VERSION 5.7 ;
  NOWIREEXTENSIONATPIN ON ;
  DIVIDERCHAR "/" ;
  BUSBITCHARS "[]" ;
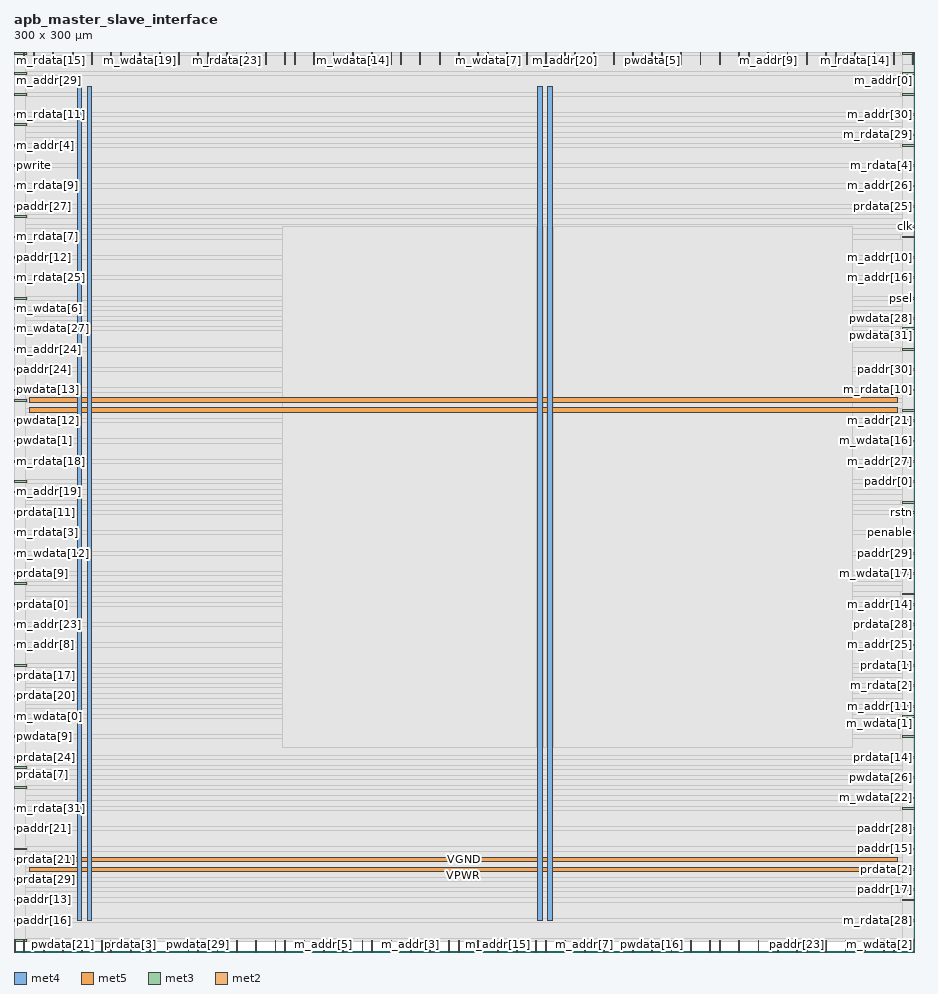
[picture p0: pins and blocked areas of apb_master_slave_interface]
MACRO apb_master_slave_interface
  CLASS BLOCK ;
  FOREIGN apb_master_slave_interface ;
  ORIGIN 0.000 0.000 ;
  SIZE 300.000 BY 300.000 ;
  PIN VGND
    DIRECTION INOUT ;
    USE GROUND ;
    PORT
      LAYER met4 ;
        RECT 24.340 10.640 25.940 288.560 ;
    END
    PORT
      LAYER met4 ;
        RECT 177.940 10.640 179.540 288.560 ;
    END
    PORT
      LAYER met5 ;
        RECT 5.280 30.030 294.640 31.630 ;
    END
    PORT
      LAYER met5 ;
        RECT 5.280 183.210 294.640 184.810 ;
    END
  END VGND
  PIN VPWR
    DIRECTION INOUT ;
    USE POWER ;
    PORT
      LAYER met4 ;
        RECT 21.040 10.640 22.640 288.560 ;
    END
    PORT
      LAYER met4 ;
        RECT 174.640 10.640 176.240 288.560 ;
    END
    PORT
      LAYER met5 ;
        RECT 5.280 26.730 294.640 28.330 ;
    END
    PORT
      LAYER met5 ;
        RECT 5.280 179.910 294.640 181.510 ;
    END
  END VPWR
  PIN clk
    DIRECTION INPUT ;
    USE SIGNAL ;
    ANTENNAGATEAREA 0.852000 ;
    PORT
      LAYER met3 ;
        RECT 296.000 241.440 300.000 242.040 ;
    END
  END clk
  PIN m_addr[0]
    DIRECTION INPUT ;
    USE SIGNAL ;
    ANTENNAGATEAREA 0.196500 ;
    PORT
      LAYER met3 ;
        RECT 296.000 292.440 300.000 293.040 ;
    END
  END m_addr[0]
  PIN m_addr[10]
    DIRECTION INPUT ;
    USE SIGNAL ;
    ANTENNAGATEAREA 0.196500 ;
    PORT
      LAYER met3 ;
        RECT 296.000 231.240 300.000 231.840 ;
    END
  END m_addr[10]
  PIN m_addr[11]
    DIRECTION INPUT ;
    USE SIGNAL ;
    ANTENNAGATEAREA 0.196500 ;
    PORT
      LAYER met3 ;
        RECT 296.000 81.640 300.000 82.240 ;
    END
  END m_addr[11]
  PIN m_addr[12]
    DIRECTION INPUT ;
    USE SIGNAL ;
    ANTENNAGATEAREA 0.196500 ;
    PORT
      LAYER met3 ;
        RECT 296.000 149.640 300.000 150.240 ;
    END
  END m_addr[12]
  PIN m_addr[13]
    DIRECTION INPUT ;
    USE SIGNAL ;
    ANTENNAGATEAREA 0.196500 ;
    PORT
      LAYER met2 ;
        RECT 283.450 0.000 283.730 4.000 ;
    END
  END m_addr[13]
  PIN m_addr[14]
    DIRECTION INPUT ;
    USE SIGNAL ;
    ANTENNAGATEAREA 0.196500 ;
    PORT
      LAYER met3 ;
        RECT 296.000 115.640 300.000 116.240 ;
    END
  END m_addr[14]
  PIN m_addr[15]
    DIRECTION INPUT ;
    USE SIGNAL ;
    ANTENNAGATEAREA 0.196500 ;
    PORT
      LAYER met2 ;
        RECT 161.090 0.000 161.370 4.000 ;
    END
  END m_addr[15]
  PIN m_addr[16]
    DIRECTION INPUT ;
    USE SIGNAL ;
    ANTENNAGATEAREA 0.126000 ;
    PORT
      LAYER met3 ;
        RECT 296.000 224.440 300.000 225.040 ;
    END
  END m_addr[16]
  PIN m_addr[17]
    DIRECTION INPUT ;
    USE SIGNAL ;
    ANTENNAGATEAREA 0.213000 ;
    PORT
      LAYER met2 ;
        RECT 83.810 296.000 84.090 300.000 ;
    END
  END m_addr[17]
  PIN m_addr[18]
    DIRECTION INPUT ;
    USE SIGNAL ;
    ANTENNAGATEAREA 0.213000 ;
    PORT
      LAYER met2 ;
        RECT 270.570 0.000 270.850 4.000 ;
    END
  END m_addr[18]
  PIN m_addr[19]
    DIRECTION INPUT ;
    USE SIGNAL ;
    ANTENNAGATEAREA 0.196500 ;
    PORT
      LAYER met3 ;
        RECT 0.000 153.040 4.000 153.640 ;
    END
  END m_addr[19]
  PIN m_addr[1]
    DIRECTION INPUT ;
    USE SIGNAL ;
    ANTENNAGATEAREA 0.196500 ;
    PORT
      LAYER met2 ;
        RECT 54.830 296.000 55.110 300.000 ;
    END
  END m_addr[1]
  PIN m_addr[20]
    DIRECTION INPUT ;
    USE SIGNAL ;
    ANTENNAGATEAREA 0.196500 ;
    PORT
      LAYER met2 ;
        RECT 183.630 296.000 183.910 300.000 ;
    END
  END m_addr[20]
  PIN m_addr[21]
    DIRECTION INPUT ;
    USE SIGNAL ;
    ANTENNAGATEAREA 0.126000 ;
    PORT
      LAYER met3 ;
        RECT 296.000 176.840 300.000 177.440 ;
    END
  END m_addr[21]
  PIN m_addr[22]
    DIRECTION INPUT ;
    USE SIGNAL ;
    ANTENNAGATEAREA 0.213000 ;
    PORT
      LAYER met2 ;
        RECT 241.590 0.000 241.870 4.000 ;
    END
  END m_addr[22]
  PIN m_addr[23]
    DIRECTION INPUT ;
    USE SIGNAL ;
    ANTENNAGATEAREA 0.196500 ;
    PORT
      LAYER met3 ;
        RECT 0.000 108.840 4.000 109.440 ;
    END
  END m_addr[23]
  PIN m_addr[24]
    DIRECTION INPUT ;
    USE SIGNAL ;
    ANTENNAGATEAREA 0.196500 ;
    PORT
      LAYER met3 ;
        RECT 0.000 200.640 4.000 201.240 ;
    END
  END m_addr[24]
  PIN m_addr[25]
    DIRECTION INPUT ;
    USE SIGNAL ;
    ANTENNAGATEAREA 0.126000 ;
    PORT
      LAYER met3 ;
        RECT 296.000 102.040 300.000 102.640 ;
    END
  END m_addr[25]
  PIN m_addr[26]
    DIRECTION INPUT ;
    USE SIGNAL ;
    ANTENNAGATEAREA 0.213000 ;
    PORT
      LAYER met3 ;
        RECT 296.000 255.040 300.000 255.640 ;
    END
  END m_addr[26]
  PIN m_addr[27]
    DIRECTION INPUT ;
    USE SIGNAL ;
    ANTENNAGATEAREA 0.196500 ;
    PORT
      LAYER met3 ;
        RECT 296.000 163.240 300.000 163.840 ;
    END
  END m_addr[27]
  PIN m_addr[28]
    DIRECTION INPUT ;
    USE SIGNAL ;
    ANTENNAGATEAREA 0.213000 ;
    PORT
      LAYER met3 ;
        RECT 0.000 183.640 4.000 184.240 ;
    END
  END m_addr[28]
  PIN m_addr[29]
    DIRECTION INPUT ;
    USE SIGNAL ;
    ANTENNAGATEAREA 0.159000 ;
    PORT
      LAYER met3 ;
        RECT 0.000 292.440 4.000 293.040 ;
    END
  END m_addr[29]
  PIN m_addr[2]
    DIRECTION INPUT ;
    USE SIGNAL ;
    ANTENNAGATEAREA 0.196500 ;
    PORT
      LAYER met2 ;
        RECT 90.250 296.000 90.530 300.000 ;
    END
  END m_addr[2]
  PIN m_addr[30]
    DIRECTION INPUT ;
    USE SIGNAL ;
    ANTENNAGATEAREA 0.196500 ;
    PORT
      LAYER met3 ;
        RECT 296.000 278.840 300.000 279.440 ;
    END
  END m_addr[30]
  PIN m_addr[31]
    DIRECTION INPUT ;
    USE SIGNAL ;
    ANTENNAGATEAREA 0.196500 ;
    PORT
      LAYER met2 ;
        RECT 80.590 0.000 80.870 4.000 ;
    END
  END m_addr[31]
  PIN m_addr[3]
    DIRECTION INPUT ;
    USE SIGNAL ;
    ANTENNAGATEAREA 0.196500 ;
    PORT
      LAYER met2 ;
        RECT 132.110 0.000 132.390 4.000 ;
    END
  END m_addr[3]
  PIN m_addr[4]
    DIRECTION INPUT ;
    USE SIGNAL ;
    ANTENNAGATEAREA 0.196500 ;
    PORT
      LAYER met3 ;
        RECT 0.000 268.640 4.000 269.240 ;
    END
  END m_addr[4]
  PIN m_addr[5]
    DIRECTION INPUT ;
    USE SIGNAL ;
    ANTENNAGATEAREA 0.196500 ;
    PORT
      LAYER met2 ;
        RECT 103.130 0.000 103.410 4.000 ;
    END
  END m_addr[5]
  PIN m_addr[6]
    DIRECTION INPUT ;
    USE SIGNAL ;
    ANTENNAGATEAREA 0.196500 ;
    PORT
      LAYER met2 ;
        RECT 128.890 296.000 129.170 300.000 ;
    END
  END m_addr[6]
  PIN m_addr[7]
    DIRECTION INPUT ;
    USE SIGNAL ;
    ANTENNAGATEAREA 0.196500 ;
    PORT
      LAYER met2 ;
        RECT 190.070 0.000 190.350 4.000 ;
    END
  END m_addr[7]
  PIN m_addr[8]
    DIRECTION INPUT ;
    USE SIGNAL ;
    ANTENNAGATEAREA 0.213000 ;
    PORT
      LAYER met3 ;
        RECT 0.000 102.040 4.000 102.640 ;
    END
  END m_addr[8]
  PIN m_addr[9]
    DIRECTION INPUT ;
    USE SIGNAL ;
    ANTENNAGATEAREA 0.196500 ;
    PORT
      LAYER met2 ;
        RECT 251.250 296.000 251.530 300.000 ;
    END
  END m_addr[9]
  PIN m_rdata[0]
    DIRECTION OUTPUT TRISTATE ;
    USE SIGNAL ;
    ANTENNADIFFAREA 0.795200 ;
    PORT
      LAYER met2 ;
        RECT 125.670 296.000 125.950 300.000 ;
    END
  END m_rdata[0]
  PIN m_rdata[10]
    DIRECTION OUTPUT TRISTATE ;
    USE SIGNAL ;
    ANTENNADIFFAREA 0.795200 ;
    PORT
      LAYER met3 ;
        RECT 296.000 187.040 300.000 187.640 ;
    END
  END m_rdata[10]
  PIN m_rdata[11]
    DIRECTION OUTPUT TRISTATE ;
    USE SIGNAL ;
    ANTENNADIFFAREA 0.795200 ;
    PORT
      LAYER met3 ;
        RECT 0.000 278.840 4.000 279.440 ;
    END
  END m_rdata[11]
  PIN m_rdata[12]
    DIRECTION OUTPUT TRISTATE ;
    USE SIGNAL ;
    ANTENNADIFFAREA 0.795200 ;
    PORT
      LAYER met2 ;
        RECT 99.910 296.000 100.190 300.000 ;
    END
  END m_rdata[12]
  PIN m_rdata[13]
    DIRECTION OUTPUT TRISTATE ;
    USE SIGNAL ;
    ANTENNADIFFAREA 0.795200 ;
    PORT
      LAYER met3 ;
        RECT 0.000 95.240 4.000 95.840 ;
    END
  END m_rdata[13]
  PIN m_rdata[14]
    DIRECTION OUTPUT TRISTATE ;
    USE SIGNAL ;
    ANTENNADIFFAREA 0.795200 ;
    PORT
      LAYER met2 ;
        RECT 280.230 296.000 280.510 300.000 ;
    END
  END m_rdata[14]
  PIN m_rdata[15]
    DIRECTION OUTPUT TRISTATE ;
    USE SIGNAL ;
    ANTENNADIFFAREA 0.795200 ;
    PORT
      LAYER met2 ;
        RECT 6.530 296.000 6.810 300.000 ;
    END
  END m_rdata[15]
  PIN m_rdata[16]
    DIRECTION OUTPUT TRISTATE ;
    USE SIGNAL ;
    ANTENNADIFFAREA 0.795200 ;
    PORT
      LAYER met2 ;
        RECT 144.990 0.000 145.270 4.000 ;
    END
  END m_rdata[16]
  PIN m_rdata[17]
    DIRECTION OUTPUT TRISTATE ;
    USE SIGNAL ;
    ANTENNADIFFAREA 0.795200 ;
    PORT
      LAYER met2 ;
        RECT 202.950 0.000 203.230 4.000 ;
    END
  END m_rdata[17]
  PIN m_rdata[18]
    DIRECTION OUTPUT TRISTATE ;
    USE SIGNAL ;
    ANTENNADIFFAREA 0.795200 ;
    PORT
      LAYER met3 ;
        RECT 0.000 163.240 4.000 163.840 ;
    END
  END m_rdata[18]
  PIN m_rdata[19]
    DIRECTION OUTPUT TRISTATE ;
    USE SIGNAL ;
    ANTENNADIFFAREA 0.795200 ;
    PORT
      LAYER met2 ;
        RECT 231.930 0.000 232.210 4.000 ;
    END
  END m_rdata[19]
  PIN m_rdata[1]
    DIRECTION OUTPUT TRISTATE ;
    USE SIGNAL ;
    ANTENNADIFFAREA 0.795200 ;
    PORT
      LAYER met2 ;
        RECT 29.070 0.000 29.350 4.000 ;
    END
  END m_rdata[1]
  PIN m_rdata[20]
    DIRECTION OUTPUT TRISTATE ;
    USE SIGNAL ;
    ANTENNADIFFAREA 0.795200 ;
    PORT
      LAYER met2 ;
        RECT 228.710 296.000 228.990 300.000 ;
    END
  END m_rdata[20]
  PIN m_rdata[21]
    DIRECTION OUTPUT TRISTATE ;
    USE SIGNAL ;
    ANTENNADIFFAREA 0.795200 ;
    PORT
      LAYER met2 ;
        RECT 90.250 0.000 90.530 4.000 ;
    END
  END m_rdata[21]
  PIN m_rdata[22]
    DIRECTION OUTPUT TRISTATE ;
    USE SIGNAL ;
    ANTENNADIFFAREA 0.795200 ;
    PORT
      LAYER met2 ;
        RECT 119.230 296.000 119.510 300.000 ;
    END
  END m_rdata[22]
  PIN m_rdata[23]
    DIRECTION OUTPUT TRISTATE ;
    USE SIGNAL ;
    ANTENNADIFFAREA 0.795200 ;
    PORT
      LAYER met2 ;
        RECT 70.930 296.000 71.210 300.000 ;
    END
  END m_rdata[23]
  PIN m_rdata[24]
    DIRECTION OUTPUT TRISTATE ;
    USE SIGNAL ;
    ANTENNADIFFAREA 0.445500 ;
    PORT
      LAYER met3 ;
        RECT 296.000 238.040 300.000 238.640 ;
    END
  END m_rdata[24]
  PIN m_rdata[25]
    DIRECTION OUTPUT TRISTATE ;
    USE SIGNAL ;
    ANTENNADIFFAREA 0.795200 ;
    PORT
      LAYER met3 ;
        RECT 0.000 224.440 4.000 225.040 ;
    END
  END m_rdata[25]
  PIN m_rdata[26]
    DIRECTION OUTPUT TRISTATE ;
    USE SIGNAL ;
    ANTENNADIFFAREA 0.795200 ;
    PORT
      LAYER met2 ;
        RECT 235.150 0.000 235.430 4.000 ;
    END
  END m_rdata[26]
  PIN m_rdata[27]
    DIRECTION OUTPUT TRISTATE ;
    USE SIGNAL ;
    ANTENNADIFFAREA 0.795200 ;
    PORT
      LAYER met3 ;
        RECT 296.000 3.440 300.000 4.040 ;
    END
  END m_rdata[27]
  PIN m_rdata[28]
    DIRECTION OUTPUT TRISTATE ;
    USE SIGNAL ;
    ANTENNADIFFAREA 0.445500 ;
    PORT
      LAYER met3 ;
        RECT 296.000 10.240 300.000 10.840 ;
    END
  END m_rdata[28]
  PIN m_rdata[29]
    DIRECTION OUTPUT TRISTATE ;
    USE SIGNAL ;
    ANTENNADIFFAREA 0.445500 ;
    PORT
      LAYER met3 ;
        RECT 296.000 272.040 300.000 272.640 ;
    END
  END m_rdata[29]
  PIN m_rdata[2]
    DIRECTION OUTPUT TRISTATE ;
    USE SIGNAL ;
    ANTENNADIFFAREA 0.795200 ;
    PORT
      LAYER met3 ;
        RECT 296.000 88.440 300.000 89.040 ;
    END
  END m_rdata[2]
  PIN m_rdata[30]
    DIRECTION OUTPUT TRISTATE ;
    USE SIGNAL ;
    ANTENNADIFFAREA 0.795200 ;
    PORT
      LAYER met2 ;
        RECT 257.690 296.000 257.970 300.000 ;
    END
  END m_rdata[30]
  PIN m_rdata[31]
    DIRECTION OUTPUT TRISTATE ;
    USE SIGNAL ;
    ANTENNADIFFAREA 0.795200 ;
    PORT
      LAYER met3 ;
        RECT 0.000 47.640 4.000 48.240 ;
    END
  END m_rdata[31]
  PIN m_rdata[3]
    DIRECTION OUTPUT TRISTATE ;
    USE SIGNAL ;
    ANTENNADIFFAREA 0.795200 ;
    PORT
      LAYER met3 ;
        RECT 0.000 139.440 4.000 140.040 ;
    END
  END m_rdata[3]
  PIN m_rdata[4]
    DIRECTION OUTPUT TRISTATE ;
    USE SIGNAL ;
    ANTENNADIFFAREA 0.795200 ;
    PORT
      LAYER met3 ;
        RECT 296.000 261.840 300.000 262.440 ;
    END
  END m_rdata[4]
  PIN m_rdata[5]
    DIRECTION OUTPUT TRISTATE ;
    USE SIGNAL ;
    ANTENNADIFFAREA 0.795200 ;
    PORT
      LAYER met2 ;
        RECT 106.350 296.000 106.630 300.000 ;
    END
  END m_rdata[5]
  PIN m_rdata[6]
    DIRECTION OUTPUT TRISTATE ;
    USE SIGNAL ;
    ANTENNADIFFAREA 0.795200 ;
    PORT
      LAYER met2 ;
        RECT 77.370 296.000 77.650 300.000 ;
    END
  END m_rdata[6]
  PIN m_rdata[7]
    DIRECTION OUTPUT TRISTATE ;
    USE SIGNAL ;
    ANTENNADIFFAREA 0.795200 ;
    PORT
      LAYER met3 ;
        RECT 0.000 238.040 4.000 238.640 ;
    END
  END m_rdata[7]
  PIN m_rdata[8]
    DIRECTION OUTPUT TRISTATE ;
    USE SIGNAL ;
    ANTENNADIFFAREA 0.795200 ;
    PORT
      LAYER met2 ;
        RECT 32.290 296.000 32.570 300.000 ;
    END
  END m_rdata[8]
  PIN m_rdata[9]
    DIRECTION OUTPUT TRISTATE ;
    USE SIGNAL ;
    ANTENNADIFFAREA 0.795200 ;
    PORT
      LAYER met3 ;
        RECT 0.000 255.040 4.000 255.640 ;
    END
  END m_rdata[9]
  PIN m_ready
    DIRECTION OUTPUT TRISTATE ;
    USE SIGNAL ;
    ANTENNADIFFAREA 0.795200 ;
    PORT
      LAYER met2 ;
        RECT 93.470 296.000 93.750 300.000 ;
    END
  END m_ready
  PIN m_req
    DIRECTION INPUT ;
    USE SIGNAL ;
    ANTENNAGATEAREA 0.196500 ;
    PORT
      LAYER met2 ;
        RECT 206.170 296.000 206.450 300.000 ;
    END
  END m_req
  PIN m_wdata[0]
    DIRECTION INPUT ;
    USE SIGNAL ;
    ANTENNAGATEAREA 0.213000 ;
    PORT
      LAYER met3 ;
        RECT 0.000 78.240 4.000 78.840 ;
    END
  END m_wdata[0]
  PIN m_wdata[10]
    DIRECTION INPUT ;
    USE SIGNAL ;
    ANTENNAGATEAREA 0.196500 ;
    PORT
      LAYER met2 ;
        RECT 170.750 296.000 171.030 300.000 ;
    END
  END m_wdata[10]
  PIN m_wdata[11]
    DIRECTION INPUT ;
    USE SIGNAL ;
    ANTENNAGATEAREA 0.196500 ;
    PORT
      LAYER met2 ;
        RECT 235.150 296.000 235.430 300.000 ;
    END
  END m_wdata[11]
  PIN m_wdata[12]
    DIRECTION INPUT ;
    USE SIGNAL ;
    ANTENNAGATEAREA 0.196500 ;
    PORT
      LAYER met3 ;
        RECT 0.000 132.640 4.000 133.240 ;
    END
  END m_wdata[12]
  PIN m_wdata[13]
    DIRECTION INPUT ;
    USE SIGNAL ;
    ANTENNAGATEAREA 0.213000 ;
    PORT
      LAYER met2 ;
        RECT 286.670 296.000 286.950 300.000 ;
    END
  END m_wdata[13]
  PIN m_wdata[14]
    DIRECTION INPUT ;
    USE SIGNAL ;
    ANTENNAGATEAREA 0.196500 ;
    PORT
      LAYER met2 ;
        RECT 112.790 296.000 113.070 300.000 ;
    END
  END m_wdata[14]
  PIN m_wdata[15]
    DIRECTION INPUT ;
    USE SIGNAL ;
    ANTENNAGATEAREA 0.213000 ;
    PORT
      LAYER met2 ;
        RECT 299.550 296.000 299.830 300.000 ;
    END
  END m_wdata[15]
  PIN m_wdata[16]
    DIRECTION INPUT ;
    USE SIGNAL ;
    ANTENNAGATEAREA 0.196500 ;
    PORT
      LAYER met3 ;
        RECT 296.000 170.040 300.000 170.640 ;
    END
  END m_wdata[16]
  PIN m_wdata[17]
    DIRECTION INPUT ;
    USE SIGNAL ;
    ANTENNAGATEAREA 0.126000 ;
    PORT
      LAYER met3 ;
        RECT 296.000 125.840 300.000 126.440 ;
    END
  END m_wdata[17]
  PIN m_wdata[18]
    DIRECTION INPUT ;
    USE SIGNAL ;
    ANTENNAGATEAREA 0.196500 ;
    PORT
      LAYER met2 ;
        RECT 244.810 296.000 245.090 300.000 ;
    END
  END m_wdata[18]
  PIN m_wdata[19]
    DIRECTION INPUT ;
    USE SIGNAL ;
    ANTENNAGATEAREA 0.196500 ;
    PORT
      LAYER met2 ;
        RECT 41.950 296.000 42.230 300.000 ;
    END
  END m_wdata[19]
  PIN m_wdata[1]
    DIRECTION INPUT ;
    USE SIGNAL ;
    ANTENNAGATEAREA 0.126000 ;
    PORT
      LAYER met3 ;
        RECT 296.000 78.240 300.000 78.840 ;
    END
  END m_wdata[1]
  PIN m_wdata[20]
    DIRECTION INPUT ;
    USE SIGNAL ;
    ANTENNAGATEAREA 0.196500 ;
    PORT
      LAYER met2 ;
        RECT 248.030 0.000 248.310 4.000 ;
    END
  END m_wdata[20]
  PIN m_wdata[21]
    DIRECTION INPUT ;
    USE SIGNAL ;
    ANTENNAGATEAREA 0.196500 ;
    PORT
      LAYER met2 ;
        RECT 119.230 0.000 119.510 4.000 ;
    END
  END m_wdata[21]
  PIN m_wdata[22]
    DIRECTION INPUT ;
    USE SIGNAL ;
    ANTENNAGATEAREA 0.126000 ;
    PORT
      LAYER met3 ;
        RECT 296.000 51.040 300.000 51.640 ;
    END
  END m_wdata[22]
  PIN m_wdata[23]
    DIRECTION INPUT ;
    USE SIGNAL ;
    ANTENNAGATEAREA 0.196500 ;
    PORT
      LAYER met2 ;
        RECT 183.630 0.000 183.910 4.000 ;
    END
  END m_wdata[23]
  PIN m_wdata[24]
    DIRECTION INPUT ;
    USE SIGNAL ;
    ANTENNAGATEAREA 0.196500 ;
    PORT
      LAYER met3 ;
        RECT 0.000 34.040 4.000 34.640 ;
    END
  END m_wdata[24]
  PIN m_wdata[25]
    DIRECTION INPUT ;
    USE SIGNAL ;
    ANTENNAGATEAREA 0.196500 ;
    PORT
      LAYER met2 ;
        RECT 154.650 0.000 154.930 4.000 ;
    END
  END m_wdata[25]
  PIN m_wdata[26]
    DIRECTION INPUT ;
    USE SIGNAL ;
    ANTENNAGATEAREA 0.196500 ;
    PORT
      LAYER met3 ;
        RECT 296.000 180.240 300.000 180.840 ;
    END
  END m_wdata[26]
  PIN m_wdata[27]
    DIRECTION INPUT ;
    USE SIGNAL ;
    ANTENNAGATEAREA 0.196500 ;
    PORT
      LAYER met3 ;
        RECT 0.000 207.440 4.000 208.040 ;
    END
  END m_wdata[27]
  PIN m_wdata[28]
    DIRECTION INPUT ;
    USE SIGNAL ;
    ANTENNAGATEAREA 0.196500 ;
    PORT
      LAYER met2 ;
        RECT 222.270 296.000 222.550 300.000 ;
    END
  END m_wdata[28]
  PIN m_wdata[29]
    DIRECTION INPUT ;
    USE SIGNAL ;
    ANTENNAGATEAREA 0.196500 ;
    PORT
      LAYER met2 ;
        RECT 96.690 0.000 96.970 4.000 ;
    END
  END m_wdata[29]
  PIN m_wdata[2]
    DIRECTION INPUT ;
    USE SIGNAL ;
    ANTENNAGATEAREA 0.196500 ;
    PORT
      LAYER met2 ;
        RECT 293.110 0.000 293.390 4.000 ;
    END
  END m_wdata[2]
  PIN m_wdata[30]
    DIRECTION INPUT ;
    USE SIGNAL ;
    ANTENNAGATEAREA 0.196500 ;
    PORT
      LAYER met2 ;
        RECT 45.170 0.000 45.450 4.000 ;
    END
  END m_wdata[30]
  PIN m_wdata[31]
    DIRECTION INPUT ;
    USE SIGNAL ;
    ANTENNAGATEAREA 0.196500 ;
    PORT
      LAYER met2 ;
        RECT 164.310 296.000 164.590 300.000 ;
    END
  END m_wdata[31]
  PIN m_wdata[3]
    DIRECTION INPUT ;
    USE SIGNAL ;
    ANTENNAGATEAREA 0.213000 ;
    PORT
      LAYER met3 ;
        RECT 296.000 299.240 300.000 299.840 ;
    END
  END m_wdata[3]
  PIN m_wdata[4]
    DIRECTION INPUT ;
    USE SIGNAL ;
    ANTENNAGATEAREA 0.126000 ;
    PORT
      LAYER met2 ;
        RECT 35.510 296.000 35.790 300.000 ;
    END
  END m_wdata[4]
  PIN m_wdata[5]
    DIRECTION INPUT ;
    USE SIGNAL ;
    ANTENNAGATEAREA 0.196500 ;
    PORT
      LAYER met2 ;
        RECT 264.130 296.000 264.410 300.000 ;
    END
  END m_wdata[5]
  PIN m_wdata[6]
    DIRECTION INPUT ;
    USE SIGNAL ;
    ANTENNAGATEAREA 0.196500 ;
    PORT
      LAYER met3 ;
        RECT 0.000 214.240 4.000 214.840 ;
    END
  END m_wdata[6]
  PIN m_wdata[7]
    DIRECTION INPUT ;
    USE SIGNAL ;
    ANTENNAGATEAREA 0.196500 ;
    PORT
      LAYER met2 ;
        RECT 157.870 296.000 158.150 300.000 ;
    END
  END m_wdata[7]
  PIN m_wdata[8]
    DIRECTION INPUT ;
    USE SIGNAL ;
    ANTENNAGATEAREA 0.196500 ;
    PORT
      LAYER met2 ;
        RECT 219.050 0.000 219.330 4.000 ;
    END
  END m_wdata[8]
  PIN m_wdata[9]
    DIRECTION INPUT ;
    USE SIGNAL ;
    ANTENNAGATEAREA 0.196500 ;
    PORT
      LAYER met2 ;
        RECT 12.970 296.000 13.250 300.000 ;
    END
  END m_wdata[9]
  PIN m_write
    DIRECTION INPUT ;
    USE SIGNAL ;
    ANTENNAGATEAREA 0.213000 ;
    PORT
      LAYER met2 ;
        RECT 254.470 0.000 254.750 4.000 ;
    END
  END m_write
  PIN paddr[0]
    DIRECTION OUTPUT TRISTATE ;
    USE SIGNAL ;
    ANTENNADIFFAREA 0.795200 ;
    PORT
      LAYER met3 ;
        RECT 296.000 156.440 300.000 157.040 ;
    END
  END paddr[0]
  PIN paddr[10]
    DIRECTION OUTPUT TRISTATE ;
    USE SIGNAL ;
    ANTENNADIFFAREA 0.445500 ;
    PORT
      LAYER met3 ;
        RECT 296.000 200.640 300.000 201.240 ;
    END
  END paddr[10]
  PIN paddr[11]
    DIRECTION OUTPUT TRISTATE ;
    USE SIGNAL ;
    ANTENNADIFFAREA 0.795200 ;
    PORT
      LAYER met3 ;
        RECT 0.000 122.440 4.000 123.040 ;
    END
  END paddr[11]
  PIN paddr[12]
    DIRECTION OUTPUT TRISTATE ;
    USE SIGNAL ;
    ANTENNADIFFAREA 0.795200 ;
    PORT
      LAYER met3 ;
        RECT 0.000 231.240 4.000 231.840 ;
    END
  END paddr[12]
  PIN paddr[13]
    DIRECTION OUTPUT TRISTATE ;
    USE SIGNAL ;
    ANTENNADIFFAREA 0.795200 ;
    PORT
      LAYER met3 ;
        RECT 0.000 17.040 4.000 17.640 ;
    END
  END paddr[13]
  PIN paddr[14]
    DIRECTION OUTPUT TRISTATE ;
    USE SIGNAL ;
    ANTENNADIFFAREA 0.445500 ;
    PORT
      LAYER met3 ;
        RECT 296.000 47.640 300.000 48.240 ;
    END
  END paddr[14]
  PIN paddr[15]
    DIRECTION OUTPUT TRISTATE ;
    USE SIGNAL ;
    ANTENNADIFFAREA 0.795200 ;
    PORT
      LAYER met3 ;
        RECT 296.000 34.040 300.000 34.640 ;
    END
  END paddr[15]
  PIN paddr[16]
    DIRECTION OUTPUT TRISTATE ;
    USE SIGNAL ;
    ANTENNADIFFAREA 0.795200 ;
    PORT
      LAYER met3 ;
        RECT 0.000 10.240 4.000 10.840 ;
    END
  END paddr[16]
  PIN paddr[17]
    DIRECTION OUTPUT TRISTATE ;
    USE SIGNAL ;
    ANTENNADIFFAREA 0.445500 ;
    PORT
      LAYER met3 ;
        RECT 296.000 20.440 300.000 21.040 ;
    END
  END paddr[17]
  PIN paddr[18]
    DIRECTION OUTPUT TRISTATE ;
    USE SIGNAL ;
    ANTENNADIFFAREA 0.795200 ;
    PORT
      LAYER met3 ;
        RECT 0.000 275.440 4.000 276.040 ;
    END
  END paddr[18]
  PIN paddr[19]
    DIRECTION OUTPUT TRISTATE ;
    USE SIGNAL ;
    ANTENNADIFFAREA 0.795200 ;
    PORT
      LAYER met2 ;
        RECT 196.510 0.000 196.790 4.000 ;
    END
  END paddr[19]
  PIN paddr[1]
    DIRECTION OUTPUT TRISTATE ;
    USE SIGNAL ;
    ANTENNADIFFAREA 0.795200 ;
    PORT
      LAYER met2 ;
        RECT 61.270 296.000 61.550 300.000 ;
    END
  END paddr[1]
  PIN paddr[20]
    DIRECTION OUTPUT TRISTATE ;
    USE SIGNAL ;
    ANTENNADIFFAREA 0.795200 ;
    PORT
      LAYER met2 ;
        RECT 186.850 296.000 187.130 300.000 ;
    END
  END paddr[20]
  PIN paddr[21]
    DIRECTION OUTPUT TRISTATE ;
    USE SIGNAL ;
    ANTENNADIFFAREA 0.795200 ;
    PORT
      LAYER met3 ;
        RECT 0.000 40.840 4.000 41.440 ;
    END
  END paddr[21]
  PIN paddr[22]
    DIRECTION OUTPUT TRISTATE ;
    USE SIGNAL ;
    ANTENNADIFFAREA 0.795200 ;
    PORT
      LAYER met2 ;
        RECT 154.650 296.000 154.930 300.000 ;
    END
  END paddr[22]
  PIN paddr[23]
    DIRECTION OUTPUT TRISTATE ;
    USE SIGNAL ;
    ANTENNADIFFAREA 0.795200 ;
    PORT
      LAYER met2 ;
        RECT 260.910 0.000 261.190 4.000 ;
    END
  END paddr[23]
  PIN paddr[24]
    DIRECTION OUTPUT TRISTATE ;
    USE SIGNAL ;
    ANTENNADIFFAREA 0.795200 ;
    PORT
      LAYER met3 ;
        RECT 0.000 193.840 4.000 194.440 ;
    END
  END paddr[24]
  PIN paddr[25]
    DIRECTION OUTPUT TRISTATE ;
    USE SIGNAL ;
    ANTENNADIFFAREA 0.795200 ;
    PORT
      LAYER met2 ;
        RECT 116.010 0.000 116.290 4.000 ;
    END
  END paddr[25]
  PIN paddr[26]
    DIRECTION OUTPUT TRISTATE ;
    USE SIGNAL ;
    ANTENNADIFFAREA 0.795200 ;
    PORT
      LAYER met2 ;
        RECT 22.630 0.000 22.910 4.000 ;
    END
  END paddr[26]
  PIN paddr[27]
    DIRECTION OUTPUT TRISTATE ;
    USE SIGNAL ;
    ANTENNADIFFAREA 0.795200 ;
    PORT
      LAYER met3 ;
        RECT 0.000 248.240 4.000 248.840 ;
    END
  END paddr[27]
  PIN paddr[28]
    DIRECTION OUTPUT TRISTATE ;
    USE SIGNAL ;
    ANTENNADIFFAREA 0.795200 ;
    PORT
      LAYER met3 ;
        RECT 296.000 40.840 300.000 41.440 ;
    END
  END paddr[28]
  PIN paddr[29]
    DIRECTION OUTPUT TRISTATE ;
    USE SIGNAL ;
    ANTENNADIFFAREA 0.445500 ;
    PORT
      LAYER met3 ;
        RECT 296.000 132.640 300.000 133.240 ;
    END
  END paddr[29]
  PIN paddr[2]
    DIRECTION OUTPUT TRISTATE ;
    USE SIGNAL ;
    ANTENNADIFFAREA 0.795200 ;
    PORT
      LAYER met2 ;
        RECT 87.030 0.000 87.310 4.000 ;
    END
  END paddr[2]
  PIN paddr[30]
    DIRECTION OUTPUT TRISTATE ;
    USE SIGNAL ;
    ANTENNADIFFAREA 0.445500 ;
    PORT
      LAYER met3 ;
        RECT 296.000 193.840 300.000 194.440 ;
    END
  END paddr[30]
  PIN paddr[31]
    DIRECTION OUTPUT TRISTATE ;
    USE SIGNAL ;
    ANTENNADIFFAREA 0.445500 ;
    PORT
      LAYER met3 ;
        RECT 296.000 17.040 300.000 17.640 ;
    END
  END paddr[31]
  PIN paddr[3]
    DIRECTION OUTPUT TRISTATE ;
    USE SIGNAL ;
    ANTENNADIFFAREA 0.795200 ;
    PORT
      LAYER met2 ;
        RECT 19.410 296.000 19.690 300.000 ;
    END
  END paddr[3]
  PIN paddr[4]
    DIRECTION OUTPUT TRISTATE ;
    USE SIGNAL ;
    ANTENNADIFFAREA 0.795200 ;
    PORT
      LAYER met2 ;
        RECT 64.490 296.000 64.770 300.000 ;
    END
  END paddr[4]
  PIN paddr[5]
    DIRECTION OUTPUT TRISTATE ;
    USE SIGNAL ;
    ANTENNADIFFAREA 0.795200 ;
    PORT
      LAYER met2 ;
        RECT 167.530 0.000 167.810 4.000 ;
    END
  END paddr[5]
  PIN paddr[6]
    DIRECTION OUTPUT TRISTATE ;
    USE SIGNAL ;
    ANTENNADIFFAREA 0.795200 ;
    PORT
      LAYER met2 ;
        RECT 67.710 0.000 67.990 4.000 ;
    END
  END paddr[6]
  PIN paddr[7]
    DIRECTION OUTPUT TRISTATE ;
    USE SIGNAL ;
    ANTENNADIFFAREA 0.795200 ;
    PORT
      LAYER met2 ;
        RECT 9.750 0.000 10.030 4.000 ;
    END
  END paddr[7]
  PIN paddr[8]
    DIRECTION OUTPUT TRISTATE ;
    USE SIGNAL ;
    ANTENNADIFFAREA 0.795200 ;
    PORT
      LAYER met2 ;
        RECT 225.490 0.000 225.770 4.000 ;
    END
  END paddr[8]
  PIN paddr[9]
    DIRECTION OUTPUT TRISTATE ;
    USE SIGNAL ;
    ANTENNADIFFAREA 0.795200 ;
    PORT
      LAYER met2 ;
        RECT 289.890 0.000 290.170 4.000 ;
    END
  END paddr[9]
  PIN pclk
    DIRECTION OUTPUT TRISTATE ;
    USE SIGNAL ;
    ANTENNADIFFAREA 0.340600 ;
    PORT
      LAYER met2 ;
        RECT 270.570 296.000 270.850 300.000 ;
    END
  END pclk
  PIN penable
    DIRECTION OUTPUT TRISTATE ;
    USE SIGNAL ;
    ANTENNADIFFAREA 0.445500 ;
    PORT
      LAYER met3 ;
        RECT 296.000 139.440 300.000 140.040 ;
    END
  END penable
  PIN prdata[0]
    DIRECTION INPUT ;
    USE SIGNAL ;
    ANTENNAGATEAREA 0.196500 ;
    PORT
      LAYER met3 ;
        RECT 0.000 115.640 4.000 116.240 ;
    END
  END prdata[0]
  PIN prdata[10]
    DIRECTION INPUT ;
    USE SIGNAL ;
    ANTENNAGATEAREA 0.196500 ;
    PORT
      LAYER met2 ;
        RECT 148.210 296.000 148.490 300.000 ;
    END
  END prdata[10]
  PIN prdata[11]
    DIRECTION INPUT ;
    USE SIGNAL ;
    ANTENNAGATEAREA 0.196500 ;
    PORT
      LAYER met3 ;
        RECT 0.000 146.240 4.000 146.840 ;
    END
  END prdata[11]
  PIN prdata[12]
    DIRECTION INPUT ;
    USE SIGNAL ;
    ANTENNAGATEAREA 0.196500 ;
    PORT
      LAYER met3 ;
        RECT 0.000 156.440 4.000 157.040 ;
    END
  END prdata[12]
  PIN prdata[13]
    DIRECTION INPUT ;
    USE SIGNAL ;
    ANTENNAGATEAREA 0.196500 ;
    PORT
      LAYER met2 ;
        RECT 51.610 0.000 51.890 4.000 ;
    END
  END prdata[13]
  PIN prdata[14]
    DIRECTION INPUT ;
    USE SIGNAL ;
    ANTENNAGATEAREA 0.196500 ;
    PORT
      LAYER met3 ;
        RECT 296.000 64.640 300.000 65.240 ;
    END
  END prdata[14]
  PIN prdata[15]
    DIRECTION INPUT ;
    USE SIGNAL ;
    ANTENNAGATEAREA 0.196500 ;
    PORT
      LAYER met2 ;
        RECT 138.550 0.000 138.830 4.000 ;
    END
  END prdata[15]
  PIN prdata[16]
    DIRECTION INPUT ;
    USE SIGNAL ;
    ANTENNAGATEAREA 0.213000 ;
    PORT
      LAYER met3 ;
        RECT 296.000 268.640 300.000 269.240 ;
    END
  END prdata[16]
  PIN prdata[17]
    DIRECTION INPUT ;
    USE SIGNAL ;
    ANTENNAGATEAREA 0.196500 ;
    PORT
      LAYER met3 ;
        RECT 0.000 91.840 4.000 92.440 ;
    END
  END prdata[17]
  PIN prdata[18]
    DIRECTION INPUT ;
    USE SIGNAL ;
    ANTENNAGATEAREA 0.196500 ;
    PORT
      LAYER met2 ;
        RECT 177.190 296.000 177.470 300.000 ;
    END
  END prdata[18]
  PIN prdata[19]
    DIRECTION INPUT ;
    USE SIGNAL ;
    ANTENNAGATEAREA 0.196500 ;
    PORT
      LAYER met2 ;
        RECT 32.290 0.000 32.570 4.000 ;
    END
  END prdata[19]
  PIN prdata[1]
    DIRECTION INPUT ;
    USE SIGNAL ;
    ANTENNAGATEAREA 0.196500 ;
    PORT
      LAYER met3 ;
        RECT 296.000 95.240 300.000 95.840 ;
    END
  END prdata[1]
  PIN prdata[20]
    DIRECTION INPUT ;
    USE SIGNAL ;
    ANTENNAGATEAREA 0.126000 ;
    PORT
      LAYER met3 ;
        RECT 0.000 85.040 4.000 85.640 ;
    END
  END prdata[20]
  PIN prdata[21]
    DIRECTION INPUT ;
    USE SIGNAL ;
    ANTENNAGATEAREA 0.196500 ;
    PORT
      LAYER met3 ;
        RECT 0.000 30.640 4.000 31.240 ;
    END
  END prdata[21]
  PIN prdata[22]
    DIRECTION INPUT ;
    USE SIGNAL ;
    ANTENNAGATEAREA 0.213000 ;
    PORT
      LAYER met3 ;
        RECT 0.000 3.440 4.000 4.040 ;
    END
  END prdata[22]
  PIN prdata[23]
    DIRECTION INPUT ;
    USE SIGNAL ;
    ANTENNAGATEAREA 0.196500 ;
    PORT
      LAYER met3 ;
        RECT 0.000 285.640 4.000 286.240 ;
    END
  END prdata[23]
  PIN prdata[24]
    DIRECTION INPUT ;
    USE SIGNAL ;
    ANTENNAGATEAREA 0.213000 ;
    PORT
      LAYER met3 ;
        RECT 0.000 64.640 4.000 65.240 ;
    END
  END prdata[24]
  PIN prdata[25]
    DIRECTION INPUT ;
    USE SIGNAL ;
    ANTENNAGATEAREA 0.126000 ;
    PORT
      LAYER met3 ;
        RECT 296.000 248.240 300.000 248.840 ;
    END
  END prdata[25]
  PIN prdata[26]
    DIRECTION INPUT ;
    USE SIGNAL ;
    ANTENNAGATEAREA 0.196500 ;
    PORT
      LAYER met2 ;
        RECT 193.290 296.000 193.570 300.000 ;
    END
  END prdata[26]
  PIN prdata[27]
    DIRECTION INPUT ;
    USE SIGNAL ;
    ANTENNAGATEAREA 0.196500 ;
    PORT
      LAYER met2 ;
        RECT 74.150 0.000 74.430 4.000 ;
    END
  END prdata[27]
  PIN prdata[28]
    DIRECTION INPUT ;
    USE SIGNAL ;
    ANTENNAGATEAREA 0.196500 ;
    PORT
      LAYER met3 ;
        RECT 296.000 108.840 300.000 109.440 ;
    END
  END prdata[28]
  PIN prdata[29]
    DIRECTION INPUT ;
    USE SIGNAL ;
    ANTENNAGATEAREA 0.159000 ;
    PORT
      LAYER met3 ;
        RECT 0.000 23.840 4.000 24.440 ;
    END
  END prdata[29]
  PIN prdata[2]
    DIRECTION INPUT ;
    USE SIGNAL ;
    ANTENNAGATEAREA 0.196500 ;
    PORT
      LAYER met3 ;
        RECT 296.000 27.240 300.000 27.840 ;
    END
  END prdata[2]
  PIN prdata[30]
    DIRECTION INPUT ;
    USE SIGNAL ;
    ANTENNAGATEAREA 0.213000 ;
    PORT
      LAYER met2 ;
        RECT 3.310 296.000 3.590 300.000 ;
    END
  END prdata[30]
  PIN prdata[31]
    DIRECTION INPUT ;
    USE SIGNAL ;
    ANTENNAGATEAREA 0.196500 ;
    PORT
      LAYER met2 ;
        RECT 264.130 0.000 264.410 4.000 ;
    END
  END prdata[31]
  PIN prdata[3]
    DIRECTION INPUT ;
    USE SIGNAL ;
    ANTENNAGATEAREA 0.196500 ;
    PORT
      LAYER met2 ;
        RECT 38.730 0.000 39.010 4.000 ;
    END
  END prdata[3]
  PIN prdata[4]
    DIRECTION INPUT ;
    USE SIGNAL ;
    ANTENNAGATEAREA 0.196500 ;
    PORT
      LAYER met2 ;
        RECT 125.670 0.000 125.950 4.000 ;
    END
  END prdata[4]
  PIN prdata[5]
    DIRECTION INPUT ;
    USE SIGNAL ;
    ANTENNAGATEAREA 0.213000 ;
    PORT
      LAYER met3 ;
        RECT 296.000 71.440 300.000 72.040 ;
    END
  END prdata[5]
  PIN prdata[6]
    DIRECTION INPUT ;
    USE SIGNAL ;
    ANTENNAGATEAREA 0.196500 ;
    PORT
      LAYER met3 ;
        RECT 296.000 285.640 300.000 286.240 ;
    END
  END prdata[6]
  PIN prdata[7]
    DIRECTION INPUT ;
    USE SIGNAL ;
    ANTENNAGATEAREA 0.196500 ;
    PORT
      LAYER met3 ;
        RECT 0.000 61.240 4.000 61.840 ;
    END
  END prdata[7]
  PIN prdata[8]
    DIRECTION INPUT ;
    USE SIGNAL ;
    ANTENNAGATEAREA 0.213000 ;
    PORT
      LAYER met2 ;
        RECT 277.010 0.000 277.290 4.000 ;
    END
  END prdata[8]
  PIN prdata[9]
    DIRECTION INPUT ;
    USE SIGNAL ;
    ANTENNAGATEAREA 0.196500 ;
    PORT
      LAYER met3 ;
        RECT 0.000 125.840 4.000 126.440 ;
    END
  END prdata[9]
  PIN pready
    DIRECTION INPUT ;
    USE SIGNAL ;
    ANTENNAGATEAREA 0.196500 ;
    PORT
      LAYER met3 ;
        RECT 296.000 119.040 300.000 119.640 ;
    END
  END pready
  PIN presetn
    DIRECTION OUTPUT TRISTATE ;
    USE SIGNAL ;
    ANTENNADIFFAREA 0.795200 ;
    PORT
      LAYER met2 ;
        RECT 3.310 0.000 3.590 4.000 ;
    END
  END presetn
  PIN psel
    DIRECTION OUTPUT TRISTATE ;
    USE SIGNAL ;
    ANTENNADIFFAREA 0.445500 ;
    PORT
      LAYER met3 ;
        RECT 296.000 217.640 300.000 218.240 ;
    END
  END psel
  PIN pwdata[0]
    DIRECTION OUTPUT TRISTATE ;
    USE SIGNAL ;
    ANTENNADIFFAREA 0.795200 ;
    PORT
      LAYER met2 ;
        RECT 293.110 296.000 293.390 300.000 ;
    END
  END pwdata[0]
  PIN pwdata[10]
    DIRECTION OUTPUT TRISTATE ;
    USE SIGNAL ;
    ANTENNADIFFAREA 0.795200 ;
    PORT
      LAYER met2 ;
        RECT 299.550 0.000 299.830 4.000 ;
    END
  END pwdata[10]
  PIN pwdata[11]
    DIRECTION OUTPUT TRISTATE ;
    USE SIGNAL ;
    ANTENNADIFFAREA 0.795200 ;
    PORT
      LAYER met2 ;
        RECT 273.790 296.000 274.070 300.000 ;
    END
  END pwdata[11]
  PIN pwdata[12]
    DIRECTION OUTPUT TRISTATE ;
    USE SIGNAL ;
    ANTENNADIFFAREA 0.795200 ;
    PORT
      LAYER met3 ;
        RECT 0.000 176.840 4.000 177.440 ;
    END
  END pwdata[12]
  PIN pwdata[13]
    DIRECTION OUTPUT TRISTATE ;
    USE SIGNAL ;
    ANTENNADIFFAREA 0.795200 ;
    PORT
      LAYER met3 ;
        RECT 0.000 187.040 4.000 187.640 ;
    END
  END pwdata[13]
  PIN pwdata[14]
    DIRECTION OUTPUT TRISTATE ;
    USE SIGNAL ;
    ANTENNADIFFAREA 0.795200 ;
    PORT
      LAYER met2 ;
        RECT 177.190 0.000 177.470 4.000 ;
    END
  END pwdata[14]
  PIN pwdata[15]
    DIRECTION OUTPUT TRISTATE ;
    USE SIGNAL ;
    ANTENNADIFFAREA 0.795200 ;
    PORT
      LAYER met2 ;
        RECT 0.090 0.000 0.370 4.000 ;
    END
  END pwdata[15]
  PIN pwdata[16]
    DIRECTION OUTPUT TRISTATE ;
    USE SIGNAL ;
    ANTENNADIFFAREA 0.795200 ;
    PORT
      LAYER met2 ;
        RECT 212.610 0.000 212.890 4.000 ;
    END
  END pwdata[16]
  PIN pwdata[17]
    DIRECTION OUTPUT TRISTATE ;
    USE SIGNAL ;
    ANTENNADIFFAREA 0.795200 ;
    PORT
      LAYER met3 ;
        RECT 0.000 217.640 4.000 218.240 ;
    END
  END pwdata[17]
  PIN pwdata[18]
    DIRECTION OUTPUT TRISTATE ;
    USE SIGNAL ;
    ANTENNADIFFAREA 0.795200 ;
    PORT
      LAYER met2 ;
        RECT 25.850 296.000 26.130 300.000 ;
    END
  END pwdata[18]
  PIN pwdata[19]
    DIRECTION OUTPUT TRISTATE ;
    USE SIGNAL ;
    ANTENNADIFFAREA 0.795200 ;
    PORT
      LAYER met2 ;
        RECT 141.770 296.000 142.050 300.000 ;
    END
  END pwdata[19]
  PIN pwdata[1]
    DIRECTION OUTPUT TRISTATE ;
    USE SIGNAL ;
    ANTENNADIFFAREA 0.795200 ;
    PORT
      LAYER met3 ;
        RECT 0.000 170.040 4.000 170.640 ;
    END
  END pwdata[1]
  PIN pwdata[20]
    DIRECTION OUTPUT TRISTATE ;
    USE SIGNAL ;
    ANTENNADIFFAREA 0.795200 ;
    PORT
      LAYER met2 ;
        RECT 58.050 0.000 58.330 4.000 ;
    END
  END pwdata[20]
  PIN pwdata[21]
    DIRECTION OUTPUT TRISTATE ;
    USE SIGNAL ;
    ANTENNADIFFAREA 0.795200 ;
    PORT
      LAYER met2 ;
        RECT 16.190 0.000 16.470 4.000 ;
    END
  END pwdata[21]
  PIN pwdata[22]
    DIRECTION OUTPUT TRISTATE ;
    USE SIGNAL ;
    ANTENNADIFFAREA 0.795200 ;
    PORT
      LAYER met2 ;
        RECT 199.730 296.000 200.010 300.000 ;
    END
  END pwdata[22]
  PIN pwdata[23]
    DIRECTION OUTPUT TRISTATE ;
    USE SIGNAL ;
    ANTENNADIFFAREA 0.795200 ;
    PORT
      LAYER met2 ;
        RECT 135.330 296.000 135.610 300.000 ;
    END
  END pwdata[23]
  PIN pwdata[24]
    DIRECTION OUTPUT TRISTATE ;
    USE SIGNAL ;
    ANTENNADIFFAREA 0.795200 ;
    PORT
      LAYER met2 ;
        RECT 148.210 0.000 148.490 4.000 ;
    END
  END pwdata[24]
  PIN pwdata[25]
    DIRECTION OUTPUT TRISTATE ;
    USE SIGNAL ;
    ANTENNADIFFAREA 0.795200 ;
    PORT
      LAYER met2 ;
        RECT 241.590 296.000 241.870 300.000 ;
    END
  END pwdata[25]
  PIN pwdata[26]
    DIRECTION OUTPUT TRISTATE ;
    USE SIGNAL ;
    ANTENNADIFFAREA 0.445500 ;
    PORT
      LAYER met3 ;
        RECT 296.000 57.840 300.000 58.440 ;
    END
  END pwdata[26]
  PIN pwdata[27]
    DIRECTION OUTPUT TRISTATE ;
    USE SIGNAL ;
    ANTENNADIFFAREA 0.795200 ;
    PORT
      LAYER met3 ;
        RECT 0.000 244.840 4.000 245.440 ;
    END
  END pwdata[27]
  PIN pwdata[28]
    DIRECTION OUTPUT TRISTATE ;
    USE SIGNAL ;
    ANTENNADIFFAREA 0.445500 ;
    PORT
      LAYER met3 ;
        RECT 296.000 210.840 300.000 211.440 ;
    END
  END pwdata[28]
  PIN pwdata[29]
    DIRECTION OUTPUT TRISTATE ;
    USE SIGNAL ;
    ANTENNADIFFAREA 0.795200 ;
    PORT
      LAYER met2 ;
        RECT 61.270 0.000 61.550 4.000 ;
    END
  END pwdata[29]
  PIN pwdata[2]
    DIRECTION OUTPUT TRISTATE ;
    USE SIGNAL ;
    ANTENNADIFFAREA 0.795200 ;
    PORT
      LAYER met2 ;
        RECT 109.570 0.000 109.850 4.000 ;
    END
  END pwdata[2]
  PIN pwdata[30]
    DIRECTION OUTPUT TRISTATE ;
    USE SIGNAL ;
    ANTENNADIFFAREA 0.795200 ;
    PORT
      LAYER met3 ;
        RECT 0.000 54.440 4.000 55.040 ;
    END
  END pwdata[30]
  PIN pwdata[31]
    DIRECTION OUTPUT TRISTATE ;
    USE SIGNAL ;
    ANTENNADIFFAREA 0.445500 ;
    PORT
      LAYER met3 ;
        RECT 296.000 207.440 300.000 208.040 ;
    END
  END pwdata[31]
  PIN pwdata[3]
    DIRECTION OUTPUT TRISTATE ;
    USE SIGNAL ;
    ANTENNADIFFAREA 0.795200 ;
    PORT
      LAYER met2 ;
        RECT 173.970 0.000 174.250 4.000 ;
    END
  END pwdata[3]
  PIN pwdata[4]
    DIRECTION OUTPUT TRISTATE ;
    USE SIGNAL ;
    ANTENNADIFFAREA 0.795200 ;
    PORT
      LAYER met2 ;
        RECT 215.830 296.000 216.110 300.000 ;
    END
  END pwdata[4]
  PIN pwdata[5]
    DIRECTION OUTPUT TRISTATE ;
    USE SIGNAL ;
    ANTENNADIFFAREA 0.795200 ;
    PORT
      LAYER met2 ;
        RECT 212.610 296.000 212.890 300.000 ;
    END
  END pwdata[5]
  PIN pwdata[6]
    DIRECTION OUTPUT TRISTATE ;
    USE SIGNAL ;
    ANTENNADIFFAREA 0.795200 ;
    PORT
      LAYER met3 ;
        RECT 0.000 299.240 4.000 299.840 ;
    END
  END pwdata[6]
  PIN pwdata[7]
    DIRECTION OUTPUT TRISTATE ;
    USE SIGNAL ;
    ANTENNADIFFAREA 0.795200 ;
    PORT
      LAYER met2 ;
        RECT 48.390 296.000 48.670 300.000 ;
    END
  END pwdata[7]
  PIN pwdata[8]
    DIRECTION OUTPUT TRISTATE ;
    USE SIGNAL ;
    ANTENNADIFFAREA 0.795200 ;
    PORT
      LAYER met2 ;
        RECT 206.170 0.000 206.450 4.000 ;
    END
  END pwdata[8]
  PIN pwdata[9]
    DIRECTION OUTPUT TRISTATE ;
    USE SIGNAL ;
    ANTENNADIFFAREA 0.795200 ;
    PORT
      LAYER met3 ;
        RECT 0.000 71.440 4.000 72.040 ;
    END
  END pwdata[9]
  PIN pwrite
    DIRECTION OUTPUT TRISTATE ;
    USE SIGNAL ;
    ANTENNADIFFAREA 0.795200 ;
    PORT
      LAYER met3 ;
        RECT 0.000 261.840 4.000 262.440 ;
    END
  END pwrite
  PIN rstn
    DIRECTION INPUT ;
    USE SIGNAL ;
    ANTENNAGATEAREA 0.213000 ;
    PORT
      LAYER met3 ;
        RECT 296.000 146.240 300.000 146.840 ;
    END
  END rstn
  OBS
      LAYER li1 ;
        RECT 5.520 10.795 294.400 288.405 ;
      LAYER met1 ;
        RECT 0.070 7.520 299.850 288.560 ;
      LAYER met2 ;
        RECT 0.100 295.720 3.030 299.725 ;
        RECT 3.870 295.720 6.250 299.725 ;
        RECT 7.090 295.720 12.690 299.725 ;
        RECT 13.530 295.720 19.130 299.725 ;
        RECT 19.970 295.720 25.570 299.725 ;
        RECT 26.410 295.720 32.010 299.725 ;
        RECT 32.850 295.720 35.230 299.725 ;
        RECT 36.070 295.720 41.670 299.725 ;
        RECT 42.510 295.720 48.110 299.725 ;
        RECT 48.950 295.720 54.550 299.725 ;
        RECT 55.390 295.720 60.990 299.725 ;
        RECT 61.830 295.720 64.210 299.725 ;
        RECT 65.050 295.720 70.650 299.725 ;
        RECT 71.490 295.720 77.090 299.725 ;
        RECT 77.930 295.720 83.530 299.725 ;
        RECT 84.370 295.720 89.970 299.725 ;
        RECT 90.810 295.720 93.190 299.725 ;
        RECT 94.030 295.720 99.630 299.725 ;
        RECT 100.470 295.720 106.070 299.725 ;
        RECT 106.910 295.720 112.510 299.725 ;
        RECT 113.350 295.720 118.950 299.725 ;
        RECT 119.790 295.720 125.390 299.725 ;
        RECT 126.230 295.720 128.610 299.725 ;
        RECT 129.450 295.720 135.050 299.725 ;
        RECT 135.890 295.720 141.490 299.725 ;
        RECT 142.330 295.720 147.930 299.725 ;
        RECT 148.770 295.720 154.370 299.725 ;
        RECT 155.210 295.720 157.590 299.725 ;
        RECT 158.430 295.720 164.030 299.725 ;
        RECT 164.870 295.720 170.470 299.725 ;
        RECT 171.310 295.720 176.910 299.725 ;
        RECT 177.750 295.720 183.350 299.725 ;
        RECT 184.190 295.720 186.570 299.725 ;
        RECT 187.410 295.720 193.010 299.725 ;
        RECT 193.850 295.720 199.450 299.725 ;
        RECT 200.290 295.720 205.890 299.725 ;
        RECT 206.730 295.720 212.330 299.725 ;
        RECT 213.170 295.720 215.550 299.725 ;
        RECT 216.390 295.720 221.990 299.725 ;
        RECT 222.830 295.720 228.430 299.725 ;
        RECT 229.270 295.720 234.870 299.725 ;
        RECT 235.710 295.720 241.310 299.725 ;
        RECT 242.150 295.720 244.530 299.725 ;
        RECT 245.370 295.720 250.970 299.725 ;
        RECT 251.810 295.720 257.410 299.725 ;
        RECT 258.250 295.720 263.850 299.725 ;
        RECT 264.690 295.720 270.290 299.725 ;
        RECT 271.130 295.720 273.510 299.725 ;
        RECT 274.350 295.720 279.950 299.725 ;
        RECT 280.790 295.720 286.390 299.725 ;
        RECT 287.230 295.720 292.830 299.725 ;
        RECT 293.670 295.720 299.270 299.725 ;
        RECT 0.100 4.280 299.820 295.720 ;
        RECT 0.650 3.555 3.030 4.280 ;
        RECT 3.870 3.555 9.470 4.280 ;
        RECT 10.310 3.555 15.910 4.280 ;
        RECT 16.750 3.555 22.350 4.280 ;
        RECT 23.190 3.555 28.790 4.280 ;
        RECT 29.630 3.555 32.010 4.280 ;
        RECT 32.850 3.555 38.450 4.280 ;
        RECT 39.290 3.555 44.890 4.280 ;
        RECT 45.730 3.555 51.330 4.280 ;
        RECT 52.170 3.555 57.770 4.280 ;
        RECT 58.610 3.555 60.990 4.280 ;
        RECT 61.830 3.555 67.430 4.280 ;
        RECT 68.270 3.555 73.870 4.280 ;
        RECT 74.710 3.555 80.310 4.280 ;
        RECT 81.150 3.555 86.750 4.280 ;
        RECT 87.590 3.555 89.970 4.280 ;
        RECT 90.810 3.555 96.410 4.280 ;
        RECT 97.250 3.555 102.850 4.280 ;
        RECT 103.690 3.555 109.290 4.280 ;
        RECT 110.130 3.555 115.730 4.280 ;
        RECT 116.570 3.555 118.950 4.280 ;
        RECT 119.790 3.555 125.390 4.280 ;
        RECT 126.230 3.555 131.830 4.280 ;
        RECT 132.670 3.555 138.270 4.280 ;
        RECT 139.110 3.555 144.710 4.280 ;
        RECT 145.550 3.555 147.930 4.280 ;
        RECT 148.770 3.555 154.370 4.280 ;
        RECT 155.210 3.555 160.810 4.280 ;
        RECT 161.650 3.555 167.250 4.280 ;
        RECT 168.090 3.555 173.690 4.280 ;
        RECT 174.530 3.555 176.910 4.280 ;
        RECT 177.750 3.555 183.350 4.280 ;
        RECT 184.190 3.555 189.790 4.280 ;
        RECT 190.630 3.555 196.230 4.280 ;
        RECT 197.070 3.555 202.670 4.280 ;
        RECT 203.510 3.555 205.890 4.280 ;
        RECT 206.730 3.555 212.330 4.280 ;
        RECT 213.170 3.555 218.770 4.280 ;
        RECT 219.610 3.555 225.210 4.280 ;
        RECT 226.050 3.555 231.650 4.280 ;
        RECT 232.490 3.555 234.870 4.280 ;
        RECT 235.710 3.555 241.310 4.280 ;
        RECT 242.150 3.555 247.750 4.280 ;
        RECT 248.590 3.555 254.190 4.280 ;
        RECT 255.030 3.555 260.630 4.280 ;
        RECT 261.470 3.555 263.850 4.280 ;
        RECT 264.690 3.555 270.290 4.280 ;
        RECT 271.130 3.555 276.730 4.280 ;
        RECT 277.570 3.555 283.170 4.280 ;
        RECT 284.010 3.555 289.610 4.280 ;
        RECT 290.450 3.555 292.830 4.280 ;
        RECT 293.670 3.555 299.270 4.280 ;
      LAYER met3 ;
        RECT 4.400 298.840 295.600 299.705 ;
        RECT 3.990 293.440 296.000 298.840 ;
        RECT 4.400 292.040 295.600 293.440 ;
        RECT 3.990 286.640 296.000 292.040 ;
        RECT 4.400 285.240 295.600 286.640 ;
        RECT 3.990 279.840 296.000 285.240 ;
        RECT 4.400 278.440 295.600 279.840 ;
        RECT 3.990 276.440 296.000 278.440 ;
        RECT 4.400 275.040 296.000 276.440 ;
        RECT 3.990 273.040 296.000 275.040 ;
        RECT 3.990 271.640 295.600 273.040 ;
        RECT 3.990 269.640 296.000 271.640 ;
        RECT 4.400 268.240 295.600 269.640 ;
        RECT 3.990 262.840 296.000 268.240 ;
        RECT 4.400 261.440 295.600 262.840 ;
        RECT 3.990 256.040 296.000 261.440 ;
        RECT 4.400 254.640 295.600 256.040 ;
        RECT 3.990 249.240 296.000 254.640 ;
        RECT 4.400 247.840 295.600 249.240 ;
        RECT 3.990 245.840 296.000 247.840 ;
        RECT 4.400 244.440 296.000 245.840 ;
        RECT 3.990 242.440 296.000 244.440 ;
        RECT 3.990 241.040 295.600 242.440 ;
        RECT 3.990 239.040 296.000 241.040 ;
        RECT 4.400 237.640 295.600 239.040 ;
        RECT 3.990 232.240 296.000 237.640 ;
        RECT 4.400 230.840 295.600 232.240 ;
        RECT 3.990 225.440 296.000 230.840 ;
        RECT 4.400 224.040 295.600 225.440 ;
        RECT 3.990 218.640 296.000 224.040 ;
        RECT 4.400 217.240 295.600 218.640 ;
        RECT 3.990 215.240 296.000 217.240 ;
        RECT 4.400 213.840 296.000 215.240 ;
        RECT 3.990 211.840 296.000 213.840 ;
        RECT 3.990 210.440 295.600 211.840 ;
        RECT 3.990 208.440 296.000 210.440 ;
        RECT 4.400 207.040 295.600 208.440 ;
        RECT 3.990 201.640 296.000 207.040 ;
        RECT 4.400 200.240 295.600 201.640 ;
        RECT 3.990 194.840 296.000 200.240 ;
        RECT 4.400 193.440 295.600 194.840 ;
        RECT 3.990 188.040 296.000 193.440 ;
        RECT 4.400 186.640 295.600 188.040 ;
        RECT 3.990 184.640 296.000 186.640 ;
        RECT 4.400 183.240 296.000 184.640 ;
        RECT 3.990 181.240 296.000 183.240 ;
        RECT 3.990 179.840 295.600 181.240 ;
        RECT 3.990 177.840 296.000 179.840 ;
        RECT 4.400 176.440 295.600 177.840 ;
        RECT 3.990 171.040 296.000 176.440 ;
        RECT 4.400 169.640 295.600 171.040 ;
        RECT 3.990 164.240 296.000 169.640 ;
        RECT 4.400 162.840 295.600 164.240 ;
        RECT 3.990 157.440 296.000 162.840 ;
        RECT 4.400 156.040 295.600 157.440 ;
        RECT 3.990 154.040 296.000 156.040 ;
        RECT 4.400 152.640 296.000 154.040 ;
        RECT 3.990 150.640 296.000 152.640 ;
        RECT 3.990 149.240 295.600 150.640 ;
        RECT 3.990 147.240 296.000 149.240 ;
        RECT 4.400 145.840 295.600 147.240 ;
        RECT 3.990 140.440 296.000 145.840 ;
        RECT 4.400 139.040 295.600 140.440 ;
        RECT 3.990 133.640 296.000 139.040 ;
        RECT 4.400 132.240 295.600 133.640 ;
        RECT 3.990 126.840 296.000 132.240 ;
        RECT 4.400 125.440 295.600 126.840 ;
        RECT 3.990 123.440 296.000 125.440 ;
        RECT 4.400 122.040 296.000 123.440 ;
        RECT 3.990 120.040 296.000 122.040 ;
        RECT 3.990 118.640 295.600 120.040 ;
        RECT 3.990 116.640 296.000 118.640 ;
        RECT 4.400 115.240 295.600 116.640 ;
        RECT 3.990 109.840 296.000 115.240 ;
        RECT 4.400 108.440 295.600 109.840 ;
        RECT 3.990 103.040 296.000 108.440 ;
        RECT 4.400 101.640 295.600 103.040 ;
        RECT 3.990 96.240 296.000 101.640 ;
        RECT 4.400 94.840 295.600 96.240 ;
        RECT 3.990 92.840 296.000 94.840 ;
        RECT 4.400 91.440 296.000 92.840 ;
        RECT 3.990 89.440 296.000 91.440 ;
        RECT 3.990 88.040 295.600 89.440 ;
        RECT 3.990 86.040 296.000 88.040 ;
        RECT 4.400 84.640 296.000 86.040 ;
        RECT 3.990 82.640 296.000 84.640 ;
        RECT 3.990 81.240 295.600 82.640 ;
        RECT 3.990 79.240 296.000 81.240 ;
        RECT 4.400 77.840 295.600 79.240 ;
        RECT 3.990 72.440 296.000 77.840 ;
        RECT 4.400 71.040 295.600 72.440 ;
        RECT 3.990 65.640 296.000 71.040 ;
        RECT 4.400 64.240 295.600 65.640 ;
        RECT 3.990 62.240 296.000 64.240 ;
        RECT 4.400 60.840 296.000 62.240 ;
        RECT 3.990 58.840 296.000 60.840 ;
        RECT 3.990 57.440 295.600 58.840 ;
        RECT 3.990 55.440 296.000 57.440 ;
        RECT 4.400 54.040 296.000 55.440 ;
        RECT 3.990 52.040 296.000 54.040 ;
        RECT 3.990 50.640 295.600 52.040 ;
        RECT 3.990 48.640 296.000 50.640 ;
        RECT 4.400 47.240 295.600 48.640 ;
        RECT 3.990 41.840 296.000 47.240 ;
        RECT 4.400 40.440 295.600 41.840 ;
        RECT 3.990 35.040 296.000 40.440 ;
        RECT 4.400 33.640 295.600 35.040 ;
        RECT 3.990 31.640 296.000 33.640 ;
        RECT 4.400 30.240 296.000 31.640 ;
        RECT 3.990 28.240 296.000 30.240 ;
        RECT 3.990 26.840 295.600 28.240 ;
        RECT 3.990 24.840 296.000 26.840 ;
        RECT 4.400 23.440 296.000 24.840 ;
        RECT 3.990 21.440 296.000 23.440 ;
        RECT 3.990 20.040 295.600 21.440 ;
        RECT 3.990 18.040 296.000 20.040 ;
        RECT 4.400 16.640 295.600 18.040 ;
        RECT 3.990 11.240 296.000 16.640 ;
        RECT 4.400 9.840 295.600 11.240 ;
        RECT 3.990 4.440 296.000 9.840 ;
        RECT 4.400 3.575 295.600 4.440 ;
      LAYER met4 ;
        RECT 89.535 68.175 174.240 241.905 ;
        RECT 176.640 68.175 177.540 241.905 ;
        RECT 179.940 68.175 279.385 241.905 ;
  END
END apb_master_slave_interface
END LIBRARY

